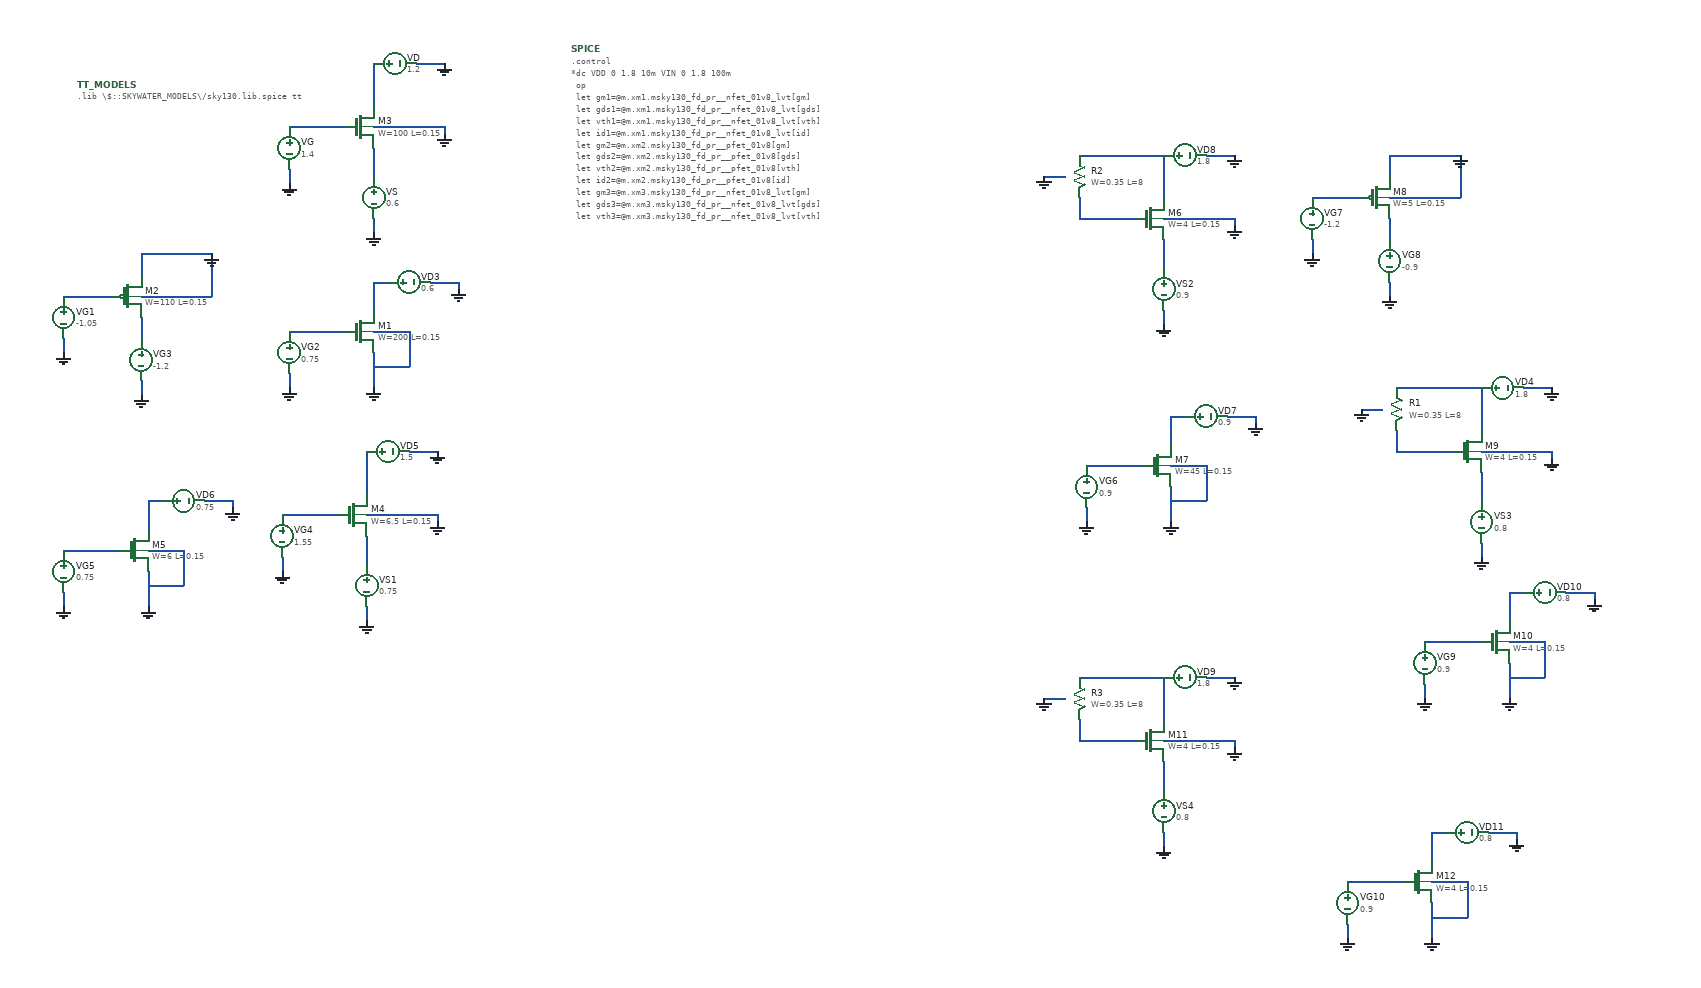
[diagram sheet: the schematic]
v {xschem version=2.9.9 file_version=1.2 }
G {}
K {}
V {}
S {}
E {}
N 490 -1560 490 -1540 { lab=GND}
N 610 -1490 610 -1470 { lab=GND}
N 610 -1590 610 -1550 { lab=#net1}
N 490 -1620 570 -1620 { lab=#net2}
N 490 -1270 490 -1250 { lab=GND}
N 610 -1300 610 -1260 { lab=GND}
N 490 -1330 570 -1330 { lab=#net3}
N 690 -1400 730 -1400 { lab=GND}
N 730 -1400 730 -1390 { lab=GND}
N 610 -1400 630 -1400 { lab=#net4}
N 610 -1400 610 -1350 { lab=#net4}
N 610 -1710 610 -1650 { lab=#net5}
N 670 -1710 710 -1710 { lab=GND}
N 610 -1620 710 -1620 { lab=GND}
N 710 -1620 710 -1610 { lab=GND}
N 610 -1260 610 -1250 { lab=GND}
N 610 -1330 660 -1330 { lab=GND}
N 660 -1330 660 -1280 { lab=GND}
N 610 -1280 660 -1280 { lab=GND}
N 280 -1380 380 -1380 { lab=GND}
N 380 -1440 380 -1380 { lab=GND}
N 280 -1440 380 -1440 { lab=GND}
N 280 -1440 280 -1410 { lab=GND}
N 170 -1320 170 -1300 { lab=GND}
N 170 -1380 240 -1380 { lab=#net6}
N 280 -1260 280 -1240 { lab=GND}
N 280 -1350 280 -1320 { lab=#net7}
N 480 -1010 480 -990 { lab=GND}
N 600 -940 600 -920 { lab=GND}
N 600 -1040 600 -1000 { lab=#net8}
N 480 -1070 560 -1070 { lab=#net9}
N 600 -1160 600 -1100 { lab=#net10}
N 660 -1160 700 -1160 { lab=GND}
N 600 -1070 700 -1070 { lab=GND}
N 700 -1070 700 -1060 { lab=GND}
N 170 -960 170 -940 { lab=GND}
N 290 -990 290 -950 { lab=GND}
N 170 -1020 250 -1020 { lab=#net11}
N 370 -1090 410 -1090 { lab=GND}
N 410 -1090 410 -1080 { lab=GND}
N 290 -1090 310 -1090 { lab=#net12}
N 290 -1090 290 -1040 { lab=#net12}
N 290 -950 290 -940 { lab=GND}
N 290 -1020 340 -1020 { lab=GND}
N 340 -1020 340 -970 { lab=GND}
N 290 -970 340 -970 { lab=GND}
N 1620 -1080 1620 -1060 { lab=GND}
N 1740 -1110 1740 -1070 { lab=GND}
N 1620 -1140 1700 -1140 { lab=#net13}
N 1820 -1210 1860 -1210 { lab=GND}
N 1860 -1210 1860 -1200 { lab=GND}
N 1740 -1210 1760 -1210 { lab=#net14}
N 1740 -1210 1740 -1160 { lab=#net14}
N 1740 -1070 1740 -1060 { lab=GND}
N 1740 -1140 1790 -1140 { lab=GND}
N 1790 -1140 1790 -1090 { lab=GND}
N 1740 -1090 1790 -1090 { lab=GND}
N 1730 -1360 1730 -1340 { lab=GND}
N 1730 -1460 1730 -1420 { lab=#net15}
N 1730 -1580 1730 -1520 { lab=#net16}
N 1790 -1580 1830 -1580 { lab=GND}
N 1730 -1490 1830 -1490 { lab=GND}
N 1830 -1490 1830 -1480 { lab=GND}
N 1610 -1580 1730 -1580 { lab=#net16}
N 1610 -1520 1610 -1490 { lab=#net17}
N 1610 -1490 1690 -1490 { lab=#net17}
N 1560 -1550 1590 -1550 { lab=GND}
N 2050 -1520 2150 -1520 { lab=GND}
N 2150 -1580 2150 -1520 { lab=GND}
N 2050 -1580 2150 -1580 { lab=GND}
N 2050 -1580 2050 -1550 { lab=GND}
N 1940 -1460 1940 -1440 { lab=GND}
N 1940 -1520 2010 -1520 { lab=#net18}
N 2050 -1400 2050 -1380 { lab=GND}
N 2050 -1490 2050 -1460 { lab=#net19}
N 2180 -1030 2180 -1010 { lab=GND}
N 2180 -1130 2180 -1090 { lab=#net20}
N 2180 -1250 2180 -1190 { lab=#net21}
N 2240 -1250 2280 -1250 { lab=GND}
N 2180 -1160 2280 -1160 { lab=GND}
N 2280 -1160 2280 -1150 { lab=GND}
N 2060 -1250 2180 -1250 { lab=#net21}
N 2060 -1190 2060 -1160 { lab=#net22}
N 2060 -1160 2140 -1160 { lab=#net22}
N 2010 -1220 2040 -1220 { lab=GND}
N 2100 -830 2100 -810 { lab=GND}
N 2220 -860 2220 -820 { lab=GND}
N 2100 -890 2180 -890 { lab=#net23}
N 2300 -960 2340 -960 { lab=GND}
N 2340 -960 2340 -950 { lab=GND}
N 2220 -960 2240 -960 { lab=#net24}
N 2220 -960 2220 -910 { lab=#net24}
N 2220 -820 2220 -810 { lab=GND}
N 2220 -890 2270 -890 { lab=GND}
N 2270 -890 2270 -840 { lab=GND}
N 2220 -840 2270 -840 { lab=GND}
N 1730 -620 1730 -600 { lab=GND}
N 1730 -720 1730 -680 { lab=#net25}
N 1730 -840 1730 -780 { lab=#net26}
N 1790 -840 1830 -840 { lab=GND}
N 1730 -750 1830 -750 { lab=GND}
N 1830 -750 1830 -740 { lab=GND}
N 1610 -840 1730 -840 { lab=#net26}
N 1610 -780 1610 -750 { lab=#net27}
N 1610 -750 1690 -750 { lab=#net27}
N 1560 -810 1590 -810 { lab=GND}
N 1990 -490 1990 -470 { lab=GND}
N 2110 -520 2110 -480 { lab=GND}
N 1990 -550 2070 -550 { lab=#net28}
N 2190 -620 2230 -620 { lab=GND}
N 2230 -620 2230 -610 { lab=GND}
N 2110 -620 2130 -620 { lab=#net29}
N 2110 -620 2110 -570 { lab=#net29}
N 2110 -480 2110 -470 { lab=GND}
N 2110 -550 2160 -550 { lab=GND}
N 2160 -550 2160 -500 { lab=GND}
N 2110 -500 2160 -500 { lab=GND}
C {devices/code.sym} 190 -1680 0 0 {name=TT_MODELS
spice_ignore=false
only_toplevel=true
format="tcleval( @value )"
value="
.lib \\\\$::SKYWATER_MODELS\\\\/sky130.lib.spice tt
"}
C {devices/code_shown.sym} 890 -1730 0 0 {name=SPICE spice_ignore=false only_toplevel=true value="

.control
*dc VDD 0 1.8 10m VIN 0 1.8 100m



	op
	let gm1=@m.xm1.msky130_fd_pr__nfet_01v8_lvt[gm]
	let gds1=@m.xm1.msky130_fd_pr__nfet_01v8_lvt[gds]
	let vth1=@m.xm1.msky130_fd_pr__nfet_01v8_lvt[vth]
	let id1=@m.xm1.msky130_fd_pr__nfet_01v8_lvt[id]

	let gm2=@m.xm2.msky130_fd_pr__pfet_01v8[gm]
	let gds2=@m.xm2.msky130_fd_pr__pfet_01v8[gds]
	let vth2=@m.xm2.msky130_fd_pr__pfet_01v8[vth]
	let id2=@m.xm2.msky130_fd_pr__pfet_01v8[id]
	
	let gm3=@m.xm3.msky130_fd_pr__nfet_01v8_lvt[gm]
	let gds3=@m.xm3.msky130_fd_pr__nfet_01v8_lvt[gds]
	let vth3=@m.xm3.msky130_fd_pr__nfet_01v8_lvt[vth]
	let id3=@m.xm3.msky130_fd_pr__nfet_01v8_lvt[id]

	let gm4=@m.xm4.msky130_fd_pr__nfet_01v8_lvt[gm]
	let gds4=@m.xm4.msky130_fd_pr__nfet_01v8_lvt[gds]
	let vth4=@m.xm4.msky130_fd_pr__nfet_01v8_lvt[vth]
	let id4=@m.xm4.msky130_fd_pr__nfet_01v8_lvt[id]
	
	let gm5=@m.xm5.msky130_fd_pr__nfet_01v8_lvt[gm]
	let gds5=@m.xm5.msky130_fd_pr__nfet_01v8_lvt[gds]
	let vth5=@m.xm5.msky130_fd_pr__nfet_01v8_lvt[vth]
	let id5=@m.xm5.msky130_fd_pr__nfet_01v8_lvt[id]
	
	let gm6=@m.xm6.msky130_fd_pr__nfet_01v8_lvt[gm]
	let gds6=@m.xm6.msky130_fd_pr__nfet_01v8_lvt[gds]
	let vth6=@m.xm6.msky130_fd_pr__nfet_01v8_lvt[vth]
	let id6=@m.xm6.msky130_fd_pr__nfet_01v8_lvt[id]

	let gm7=@m.xm7.msky130_fd_pr__nfet_01v8_lvt[gm]
	let gds7=@m.xm7.msky130_fd_pr__nfet_01v8_lvt[gds]
	let vth7=@m.xm7.msky130_fd_pr__nfet_01v8_lvt[vth]
	let id7=@m.xm7.msky130_fd_pr__nfet_01v8_lvt[id]

	let gm8=@m.xm8.msky130_fd_pr__pfet_01v8[gm]
	let gds8=@m.xm8.msky130_fd_pr__pfet_01v8[gds]
	let vth8=@m.xm8.msky130_fd_pr__pfet_01v8[vth]
	let id8=@m.xm8.msky130_fd_pr__pfet_01v8[id]

	let gm9=@m.xm9.msky130_fd_pr__nfet_01v8_lvt[gm]
	let gds9=@m.xm9.msky130_fd_pr__nfet_01v8_lvt[gds]
	let vth9=@m.xm9.msky130_fd_pr__nfet_01v8_lvt[vth]
	let id9=@m.xm9.msky130_fd_pr__nfet_01v8_lvt[id]
	
	let gm10=@m.xm10.msky130_fd_pr__nfet_01v8_lvt[gm]
	let gds10=@m.xm10.msky130_fd_pr__nfet_01v8_lvt[gds]
	let vth10=@m.xm10.msky130_fd_pr__nfet_01v8_lvt[vth]
	let id10=@m.xm10.msky130_fd_pr__nfet_01v8_lvt[id]
	
	let gm11=@m.xm11.msky130_fd_pr__nfet_01v8_lvt[gm]
	let gds11=@m.xm11.msky130_fd_pr__nfet_01v8_lvt[gds]
	let vth11=@m.xm11.msky130_fd_pr__nfet_01v8_lvt[vth]
	let id11=@m.xm11.msky130_fd_pr__nfet_01v8_lvt[id]

	let gm12=@m.xm12.msky130_fd_pr__nfet_01v8_lvt[gm]
	let gds12=@m.xm12.msky130_fd_pr__nfet_01v8_lvt[gds]
	let vth12=@m.xm12.msky130_fd_pr__nfet_01v8_lvt[vth]
	let id12=@m.xm12.msky130_fd_pr__nfet_01v8_lvt[id]
*display


print gm1
print gds1
print vth1
print id1



print gm2
print gds2
print vth2
print id2

print gm3
print gds3
print vth3
print id3

print gm4
print gds4
print vth4
print id4

print gm5
print gds5
print vth5
print id5

print gm6
print gds6
print vth6
print id6

print gm7
print gds7
print vth7
print id7

print gm8
print gds8
print vth8
print id8

print gm9
print gds9
print vth9
print id9

print gm10
print gds10
print vth10
print id10

print gm11
print gds11
print vth11
print id11

print gm12
print gds12
print vth12
print id12


.endc
"}
C {devices/vsource.sym} 610 -1520 0 0 {name=VS value=0.6}
C {devices/vsource.sym} 490 -1590 0 0 {name=VG value=1.4}
C {devices/vsource.sym} 640 -1710 3 0 {name=VD value=1.2}
C {devices/gnd.sym} 710 -1710 0 0 {name=l2 lab=GND}
C {devices/gnd.sym} 610 -1470 0 0 {name=l3 lab=GND}
C {devices/gnd.sym} 490 -1540 0 0 {name=l4 lab=GND}
C {devices/vsource.sym} 490 -1300 0 0 {name=VG2 value=0.75}
C {devices/vsource.sym} 660 -1400 3 0 {name=VD3 value=0.6}
C {devices/gnd.sym} 730 -1390 0 0 {name=l1 lab=GND}
C {devices/gnd.sym} 610 -1250 0 0 {name=l5 lab=GND}
C {devices/gnd.sym} 490 -1250 0 0 {name=l6 lab=GND}
C {xschem_sky130/sky130_fd_pr/nfet_01v8_lvt.sym} 590 -1620 0 0 {name=M3
L=0.15
W=100
nf=10
mult=1
ad="'int((nf+1)/2) * W/nf * 0.29'" 
pd="'2*int((nf+1)/2) * (W/nf + 0.29)'"
as="'int((nf+2)/2) * W/nf * 0.29'" 
ps="'2*int((nf+2)/2) * (W/nf + 0.29)'"
nrd="'0.29 / W'" nrs="'0.29 / W'"
sa=0 sb=0 sd=0
model=nfet_01v8_lvt
spiceprefix=X
}
C {xschem_sky130/sky130_fd_pr/nfet_01v8_lvt.sym} 590 -1330 0 0 {name=M1
L=0.15
W=200
nf=20
mult=1
ad="'int((nf+1)/2) * W/nf * 0.29'" 
pd="'2*int((nf+1)/2) * (W/nf + 0.29)'"
as="'int((nf+2)/2) * W/nf * 0.29'" 
ps="'2*int((nf+2)/2) * (W/nf + 0.29)'"
nrd="'0.29 / W'" nrs="'0.29 / W'"
sa=0 sb=0 sd=0
model=nfet_01v8_lvt
spiceprefix=X
}
C {devices/gnd.sym} 710 -1610 0 0 {name=l7 lab=GND}
C {devices/vsource.sym} 170 -1350 0 0 {name=VG1 value=-1.05}
C {devices/gnd.sym} 170 -1300 0 0 {name=l8 lab=GND}
C {devices/vsource.sym} 280 -1290 0 0 {name=VG3 value=-1.2}
C {devices/gnd.sym} 280 -1240 0 0 {name=l9 lab=GND}
C {devices/gnd.sym} 380 -1440 3 0 {name=l10 lab=GND}
C {xschem_sky130/sky130_fd_pr/pfet_01v8.sym} 260 -1380 0 0 {name=M2
L=0.15
W=110
nf=11
mult=1
ad="'int((nf+1)/2) * W/nf * 0.29'" 
pd="'2*int((nf+1)/2) * (W/nf + 0.29)'"
as="'int((nf+2)/2) * W/nf * 0.29'" 
ps="'2*int((nf+2)/2) * (W/nf + 0.29)'"
nrd="'0.29 / W'" nrs="'0.29 / W'"
sa=0 sb=0 sd=0
model=pfet_01v8
spiceprefix=X
}
C {devices/vsource.sym} 600 -970 0 0 {name=VS1 value=0.75}
C {devices/vsource.sym} 480 -1040 0 0 {name=VG4 value=1.55}
C {devices/vsource.sym} 630 -1160 3 0 {name=VD5 value=1.5}
C {devices/gnd.sym} 700 -1160 0 0 {name=l11 lab=GND}
C {devices/gnd.sym} 600 -920 0 0 {name=l12 lab=GND}
C {devices/gnd.sym} 480 -990 0 0 {name=l13 lab=GND}
C {xschem_sky130/sky130_fd_pr/nfet_01v8_lvt.sym} 580 -1070 0 0 {name=M4
L=0.15
W=6.5
nf=1
mult=1
ad="'int((nf+1)/2) * W/nf * 0.29'" 
pd="'2*int((nf+1)/2) * (W/nf + 0.29)'"
as="'int((nf+2)/2) * W/nf * 0.29'" 
ps="'2*int((nf+2)/2) * (W/nf + 0.29)'"
nrd="'0.29 / W'" nrs="'0.29 / W'"
sa=0 sb=0 sd=0
model=nfet_01v8_lvt
spiceprefix=X
}
C {devices/gnd.sym} 700 -1060 0 0 {name=l14 lab=GND}
C {devices/vsource.sym} 170 -990 0 0 {name=VG5 value=0.75}
C {devices/vsource.sym} 340 -1090 3 0 {name=VD6 value=0.75}
C {devices/gnd.sym} 410 -1080 0 0 {name=l15 lab=GND}
C {devices/gnd.sym} 290 -940 0 0 {name=l16 lab=GND}
C {devices/gnd.sym} 170 -940 0 0 {name=l17 lab=GND}
C {xschem_sky130/sky130_fd_pr/nfet_01v8_lvt.sym} 270 -1020 0 0 {name=M5
L=0.15
W=6
nf=1
mult=1
ad="'int((nf+1)/2) * W/nf * 0.29'" 
pd="'2*int((nf+1)/2) * (W/nf + 0.29)'"
as="'int((nf+2)/2) * W/nf * 0.29'" 
ps="'2*int((nf+2)/2) * (W/nf + 0.29)'"
nrd="'0.29 / W'" nrs="'0.29 / W'"
sa=0 sb=0 sd=0
model=nfet_01v8_lvt
spiceprefix=X
}
C {devices/vsource.sym} 1620 -1110 0 0 {name=VG6 value=0.9}
C {devices/vsource.sym} 1790 -1210 3 0 {name=VD7 value=0.9}
C {devices/gnd.sym} 1860 -1200 0 0 {name=l18 lab=GND}
C {devices/gnd.sym} 1740 -1060 0 0 {name=l19 lab=GND}
C {devices/gnd.sym} 1620 -1060 0 0 {name=l20 lab=GND}
C {xschem_sky130/sky130_fd_pr/nfet_01v8_lvt.sym} 1720 -1140 0 0 {name=M7
L=0.15
W=45
nf=9
mult=1
ad="'int((nf+1)/2) * W/nf * 0.29'" 
pd="'2*int((nf+1)/2) * (W/nf + 0.29)'"
as="'int((nf+2)/2) * W/nf * 0.29'" 
ps="'2*int((nf+2)/2) * (W/nf + 0.29)'"
nrd="'0.29 / W'" nrs="'0.29 / W'"
sa=0 sb=0 sd=0
model=nfet_01v8_lvt
spiceprefix=X
}
C {devices/vsource.sym} 1730 -1390 0 0 {name=VS2 value=0.9}
C {devices/vsource.sym} 1760 -1580 3 0 {name=VD8 value=1.8}
C {devices/gnd.sym} 1830 -1580 0 0 {name=l21 lab=GND}
C {devices/gnd.sym} 1730 -1340 0 0 {name=l22 lab=GND}
C {xschem_sky130/sky130_fd_pr/nfet_01v8_lvt.sym} 1710 -1490 0 0 {name=M6
L=0.15
W=4
nf=1
mult=3
ad="'int((nf+1)/2) * W/nf * 0.29'" 
pd="'2*int((nf+1)/2) * (W/nf + 0.29)'"
as="'int((nf+2)/2) * W/nf * 0.29'" 
ps="'2*int((nf+2)/2) * (W/nf + 0.29)'"
nrd="'0.29 / W'" nrs="'0.29 / W'"
sa=0 sb=0 sd=0
model=nfet_01v8_lvt
spiceprefix=X
}
C {devices/gnd.sym} 1830 -1480 0 0 {name=l24 lab=GND}
C {xschem_sky130/sky130_fd_pr/res_high_po_0p35.sym} 1610 -1550 0 0 {name=R2
W=0.35
L=8
model=res_high_po_0p35
spiceprefix=X
mult=1}
C {devices/gnd.sym} 1560 -1550 0 0 {name=l23 lab=GND}
C {devices/vsource.sym} 1940 -1490 0 0 {name=VG7 value=-1.2}
C {devices/gnd.sym} 1940 -1440 0 0 {name=l25 lab=GND}
C {devices/vsource.sym} 2050 -1430 0 0 {name=VG8 value=-0.9}
C {devices/gnd.sym} 2050 -1380 0 0 {name=l26 lab=GND}
C {devices/gnd.sym} 2150 -1580 3 0 {name=l27 lab=GND}
C {xschem_sky130/sky130_fd_pr/pfet_01v8.sym} 2030 -1520 0 0 {name=M8
L=0.15
W=5
nf=1
mult=16
ad="'int((nf+1)/2) * W/nf * 0.29'" 
pd="'2*int((nf+1)/2) * (W/nf + 0.29)'"
as="'int((nf+2)/2) * W/nf * 0.29'" 
ps="'2*int((nf+2)/2) * (W/nf + 0.29)'"
nrd="'0.29 / W'" nrs="'0.29 / W'"
sa=0 sb=0 sd=0
model=pfet_01v8
spiceprefix=X
}
C {devices/vsource.sym} 2180 -1060 0 0 {name=VS3 value=0.8}
C {devices/vsource.sym} 2210 -1250 3 0 {name=VD4 value=1.8}
C {devices/gnd.sym} 2280 -1250 0 0 {name=l28 lab=GND}
C {devices/gnd.sym} 2180 -1010 0 0 {name=l29 lab=GND}
C {xschem_sky130/sky130_fd_pr/nfet_01v8_lvt.sym} 2160 -1160 0 0 {name=M9
L=0.15
W=4
nf=1
mult=10
ad="'int((nf+1)/2) * W/nf * 0.29'" 
pd="'2*int((nf+1)/2) * (W/nf + 0.29)'"
as="'int((nf+2)/2) * W/nf * 0.29'" 
ps="'2*int((nf+2)/2) * (W/nf + 0.29)'"
nrd="'0.29 / W'" nrs="'0.29 / W'"
sa=0 sb=0 sd=0
model=nfet_01v8_lvt
spiceprefix=X
}
C {devices/gnd.sym} 2280 -1150 0 0 {name=l30 lab=GND}
C {xschem_sky130/sky130_fd_pr/res_high_po_0p35.sym} 2060 -1220 0 0 {name=R1
W=0.35
L=8
model=res_high_po_0p35
spiceprefix=X
mult=1}
C {devices/gnd.sym} 2010 -1220 0 0 {name=l31 lab=GND}
C {devices/vsource.sym} 2100 -860 0 0 {name=VG9 value=0.9}
C {devices/vsource.sym} 2270 -960 3 0 {name=VD10 value=0.8}
C {devices/gnd.sym} 2340 -950 0 0 {name=l32 lab=GND}
C {devices/gnd.sym} 2220 -810 0 0 {name=l33 lab=GND}
C {devices/gnd.sym} 2100 -810 0 0 {name=l34 lab=GND}
C {xschem_sky130/sky130_fd_pr/nfet_01v8_lvt.sym} 2200 -890 0 0 {name=M10
L=0.15
W=4
nf=1
mult=12
ad="'int((nf+1)/2) * W/nf * 0.29'" 
pd="'2*int((nf+1)/2) * (W/nf + 0.29)'"
as="'int((nf+2)/2) * W/nf * 0.29'" 
ps="'2*int((nf+2)/2) * (W/nf + 0.29)'"
nrd="'0.29 / W'" nrs="'0.29 / W'"
sa=0 sb=0 sd=0
model=nfet_01v8_lvt
spiceprefix=X
}
C {devices/vsource.sym} 1730 -650 0 0 {name=VS4 value=0.8}
C {devices/vsource.sym} 1760 -840 3 0 {name=VD9 value=1.8}
C {devices/gnd.sym} 1830 -840 0 0 {name=l35 lab=GND}
C {devices/gnd.sym} 1730 -600 0 0 {name=l36 lab=GND}
C {xschem_sky130/sky130_fd_pr/nfet_01v8_lvt.sym} 1710 -750 0 0 {name=M11
L=0.15
W=4
nf=1
mult=50
ad="'int((nf+1)/2) * W/nf * 0.29'" 
pd="'2*int((nf+1)/2) * (W/nf + 0.29)'"
as="'int((nf+2)/2) * W/nf * 0.29'" 
ps="'2*int((nf+2)/2) * (W/nf + 0.29)'"
nrd="'0.29 / W'" nrs="'0.29 / W'"
sa=0 sb=0 sd=0
model=nfet_01v8_lvt
spiceprefix=X
}
C {devices/gnd.sym} 1830 -740 0 0 {name=l37 lab=GND}
C {xschem_sky130/sky130_fd_pr/res_high_po_0p35.sym} 1610 -810 0 0 {name=R3
W=0.35
L=8
model=res_high_po_0p35
spiceprefix=X
mult=1}
C {devices/gnd.sym} 1560 -810 0 0 {name=l38 lab=GND}
C {devices/vsource.sym} 1990 -520 0 0 {name=VG10 value=0.9}
C {devices/vsource.sym} 2160 -620 3 0 {name=VD11 value=0.8}
C {devices/gnd.sym} 2230 -610 0 0 {name=l39 lab=GND}
C {devices/gnd.sym} 2110 -470 0 0 {name=l40 lab=GND}
C {devices/gnd.sym} 1990 -470 0 0 {name=l41 lab=GND}
C {xschem_sky130/sky130_fd_pr/nfet_01v8_lvt.sym} 2090 -550 0 0 {name=M12
L=0.15
W=4
nf=1
mult=50
ad="'int((nf+1)/2) * W/nf * 0.29'" 
pd="'2*int((nf+1)/2) * (W/nf + 0.29)'"
as="'int((nf+2)/2) * W/nf * 0.29'" 
ps="'2*int((nf+2)/2) * (W/nf + 0.29)'"
nrd="'0.29 / W'" nrs="'0.29 / W'"
sa=0 sb=0 sd=0
model=nfet_01v8_lvt
spiceprefix=X
}
